VERSION 5.7 ;
  NOWIREEXTENSIONATPIN ON ;
  DIVIDERCHAR "/" ;
  BUSBITCHARS "[]" ;
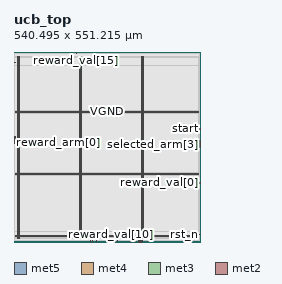
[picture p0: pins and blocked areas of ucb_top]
MACRO ucb_top
  CLASS BLOCK ;
  FOREIGN ucb_top ;
  ORIGIN 0.000 0.000 ;
  SIZE 540.495 BY 551.215 ;
  PIN VGND
    USE GROUND ;
    PORT
      LAYER met5 ;
        RECT 5.280 378.380 534.760 379.980 ;
    END
    PORT
      LAYER met5 ;
        RECT 5.280 198.380 534.760 199.980 ;
    END
    PORT
      LAYER met5 ;
        RECT 5.280 18.380 534.760 19.980 ;
    END
    PORT
      LAYER met4 ;
        RECT 373.020 10.640 374.620 538.800 ;
    END
    PORT
      LAYER met4 ;
        RECT 193.020 10.640 194.620 538.800 ;
    END
    PORT
      LAYER met4 ;
        RECT 13.020 10.640 14.620 538.800 ;
    END
  END VGND
  PIN VPWR
    USE POWER ;
    PORT
      LAYER met5 ;
        RECT 5.280 375.080 534.760 376.680 ;
    END
    PORT
      LAYER met5 ;
        RECT 5.280 195.080 534.760 196.680 ;
    END
    PORT
      LAYER met5 ;
        RECT 5.280 15.080 534.760 16.680 ;
    END
    PORT
      LAYER met4 ;
        RECT 369.720 10.640 371.320 538.800 ;
    END
    PORT
      LAYER met4 ;
        RECT 189.720 10.640 191.320 538.800 ;
    END
    PORT
      LAYER met4 ;
        RECT 9.720 10.640 11.320 538.800 ;
    END
  END VPWR
  PIN clk
    PORT
      LAYER met3 ;
        RECT 0.000 520.240 4.000 520.840 ;
    END
  END clk
  PIN reward_arm[0]
    PORT
      LAYER met3 ;
        RECT 0.000 289.040 4.000 289.640 ;
    END
  END reward_arm[0]
  PIN reward_arm[1]
    PORT
      LAYER met3 ;
        RECT 0.000 295.840 4.000 296.440 ;
    END
  END reward_arm[1]
  PIN reward_arm[2]
    PORT
      LAYER met3 ;
        RECT 0.000 292.440 4.000 293.040 ;
    END
  END reward_arm[2]
  PIN reward_arm[3]
    PORT
      LAYER met3 ;
        RECT 0.000 299.240 4.000 299.840 ;
    END
  END reward_arm[3]
  PIN reward_arm[4]
    PORT
      LAYER met3 ;
        RECT 0.000 306.040 4.000 306.640 ;
    END
  END reward_arm[4]
  PIN reward_arm[5]
    PORT
      LAYER met3 ;
        RECT 0.000 302.640 4.000 303.240 ;
    END
  END reward_arm[5]
  PIN reward_val[0]
    PORT
      LAYER met3 ;
        RECT 536.495 173.440 540.495 174.040 ;
    END
  END reward_val[0]
  PIN reward_val[10]
    PORT
      LAYER met2 ;
        RECT 280.230 0.000 280.510 4.000 ;
    END
  END reward_val[10]
  PIN reward_val[11]
    PORT
      LAYER met2 ;
        RECT 267.350 0.000 267.630 4.000 ;
    END
  END reward_val[11]
  PIN reward_val[12]
    PORT
      LAYER met2 ;
        RECT 238.370 0.000 238.650 4.000 ;
    END
  END reward_val[12]
  PIN reward_val[13]
    PORT
      LAYER met2 ;
        RECT 222.270 0.000 222.550 4.000 ;
    END
  END reward_val[13]
  PIN reward_val[14]
    PORT
      LAYER met2 ;
        RECT 228.710 0.000 228.990 4.000 ;
    END
  END reward_val[14]
  PIN reward_val[15]
    PORT
      LAYER met2 ;
        RECT 180.410 547.215 180.690 551.215 ;
    END
  END reward_val[15]
  PIN reward_val[1]
    PORT
      LAYER met3 ;
        RECT 536.495 170.040 540.495 170.640 ;
    END
  END reward_val[1]
  PIN reward_val[2]
    PORT
      LAYER met2 ;
        RECT 370.390 0.000 370.670 4.000 ;
    END
  END reward_val[2]
  PIN reward_val[3]
    PORT
      LAYER met2 ;
        RECT 367.170 0.000 367.450 4.000 ;
    END
  END reward_val[3]
  PIN reward_val[4]
    PORT
      LAYER met2 ;
        RECT 373.610 0.000 373.890 4.000 ;
    END
  END reward_val[4]
  PIN reward_val[5]
    PORT
      LAYER met2 ;
        RECT 363.950 0.000 364.230 4.000 ;
    END
  END reward_val[5]
  PIN reward_val[6]
    PORT
      LAYER met2 ;
        RECT 360.730 0.000 361.010 4.000 ;
    END
  END reward_val[6]
  PIN reward_val[7]
    PORT
      LAYER met2 ;
        RECT 351.070 0.000 351.350 4.000 ;
    END
  END reward_val[7]
  PIN reward_val[8]
    PORT
      LAYER met2 ;
        RECT 341.410 0.000 341.690 4.000 ;
    END
  END reward_val[8]
  PIN reward_val[9]
    PORT
      LAYER met2 ;
        RECT 299.550 0.000 299.830 4.000 ;
    END
  END reward_val[9]
  PIN reward_valid
    PORT
      LAYER met3 ;
        RECT 0.000 285.640 4.000 286.240 ;
    END
  END reward_valid
  PIN rst_n
    PORT
      LAYER met3 ;
        RECT 536.495 20.440 540.495 21.040 ;
    END
  END rst_n
  PIN selected_arm[0]
    PORT
      LAYER met3 ;
        RECT 536.495 275.440 540.495 276.040 ;
    END
  END selected_arm[0]
  PIN selected_arm[1]
    PORT
      LAYER met3 ;
        RECT 536.495 278.840 540.495 279.440 ;
    END
  END selected_arm[1]
  PIN selected_arm[2]
    PORT
      LAYER met3 ;
        RECT 536.495 285.640 540.495 286.240 ;
    END
  END selected_arm[2]
  PIN selected_arm[3]
    PORT
      LAYER met3 ;
        RECT 536.495 282.240 540.495 282.840 ;
    END
  END selected_arm[3]
  PIN selected_arm[4]
    PORT
      LAYER met3 ;
        RECT 536.495 292.440 540.495 293.040 ;
    END
  END selected_arm[4]
  PIN selected_arm[5]
    PORT
      LAYER met3 ;
        RECT 536.495 289.040 540.495 289.640 ;
    END
  END selected_arm[5]
  PIN start
    PORT
      LAYER met3 ;
        RECT 536.495 329.840 540.495 330.440 ;
    END
  END start
  PIN valid_out
    PORT
      LAYER met3 ;
        RECT 536.495 326.440 540.495 327.040 ;
    END
  END valid_out
  OBS
      LAYER met1 ;
        RECT 0.070 10.640 538.130 538.800 ;
      LAYER met2 ;
        RECT 0.090 546.935 180.130 547.810 ;
        RECT 180.970 546.935 538.100 547.810 ;
        RECT 0.090 4.280 538.100 546.935 ;
        RECT 0.090 4.000 221.990 4.280 ;
        RECT 222.830 4.000 228.430 4.280 ;
        RECT 229.270 4.000 238.090 4.280 ;
        RECT 238.930 4.000 267.070 4.280 ;
        RECT 267.910 4.000 279.950 4.280 ;
        RECT 280.790 4.000 299.270 4.280 ;
        RECT 300.110 4.000 341.130 4.280 ;
        RECT 341.970 4.000 350.790 4.280 ;
        RECT 351.630 4.000 360.450 4.280 ;
        RECT 361.290 4.000 363.670 4.280 ;
        RECT 364.510 4.000 366.890 4.280 ;
        RECT 367.730 4.000 370.110 4.280 ;
        RECT 370.950 4.000 373.330 4.280 ;
        RECT 374.170 4.000 538.100 4.280 ;
      LAYER met3 ;
        RECT 0.065 521.240 537.675 538.725 ;
        RECT 4.400 519.840 537.675 521.240 ;
        RECT 0.065 330.840 537.675 519.840 ;
        RECT 0.065 329.440 536.095 330.840 ;
        RECT 0.065 327.440 537.675 329.440 ;
        RECT 0.065 326.040 536.095 327.440 ;
        RECT 0.065 307.040 537.675 326.040 ;
        RECT 4.400 305.640 537.675 307.040 ;
        RECT 0.065 303.640 537.675 305.640 ;
        RECT 4.400 302.240 537.675 303.640 ;
        RECT 0.065 300.240 537.675 302.240 ;
        RECT 4.400 298.840 537.675 300.240 ;
        RECT 0.065 296.840 537.675 298.840 ;
        RECT 4.400 295.440 537.675 296.840 ;
        RECT 0.065 293.440 537.675 295.440 ;
        RECT 4.400 292.040 536.095 293.440 ;
        RECT 0.065 290.040 537.675 292.040 ;
        RECT 4.400 288.640 536.095 290.040 ;
        RECT 0.065 286.640 537.675 288.640 ;
        RECT 4.400 285.240 536.095 286.640 ;
        RECT 0.065 283.240 537.675 285.240 ;
        RECT 0.065 281.840 536.095 283.240 ;
        RECT 0.065 279.840 537.675 281.840 ;
        RECT 0.065 278.440 536.095 279.840 ;
        RECT 0.065 276.440 537.675 278.440 ;
        RECT 0.065 275.040 536.095 276.440 ;
        RECT 0.065 174.440 537.675 275.040 ;
        RECT 0.065 173.040 536.095 174.440 ;
        RECT 0.065 171.040 537.675 173.040 ;
        RECT 0.065 169.640 536.095 171.040 ;
        RECT 0.065 21.440 537.675 169.640 ;
        RECT 0.065 20.040 536.095 21.440 ;
        RECT 0.065 10.715 537.675 20.040 ;
      LAYER met4 ;
        RECT 1.215 13.095 9.320 534.985 ;
        RECT 11.720 13.095 12.620 534.985 ;
        RECT 15.020 13.095 189.320 534.985 ;
        RECT 191.720 13.095 192.620 534.985 ;
        RECT 195.020 13.095 369.320 534.985 ;
        RECT 371.720 13.095 372.620 534.985 ;
        RECT 375.020 13.095 534.210 534.985 ;
      LAYER met5 ;
        RECT 0.580 381.580 534.860 512.500 ;
        RECT 0.580 373.480 3.680 381.580 ;
        RECT 0.580 201.580 534.860 373.480 ;
        RECT 0.580 193.480 3.680 201.580 ;
        RECT 0.580 31.500 534.860 193.480 ;
  END
END ucb_top
END LIBRARY

